VERSION 5.7 ;
  NOWIREEXTENSIONATPIN ON ;
  DIVIDERCHAR "/" ;
  BUSBITCHARS "[]" ;
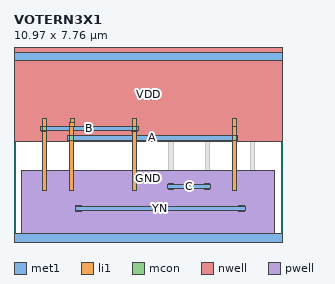
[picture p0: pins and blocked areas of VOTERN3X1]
MACRO VOTERN3X1
  CLASS CORE ;
  FOREIGN VOTERN3X1 ;
  ORIGIN 0.000 0.000 ;
  SIZE 10.970 BY 7.760 ;
  SYMMETRY X Y ;
  SITE unitrh ;
  PIN YN
    DIRECTION OUTPUT ;
    USE SIGNAL ;
    ANTENNADIFFAREA 1.734950 ;
    PORT
      LAYER met1 ;
        RECT 2.525 1.445 2.755 1.475 ;
        RECT 5.855 1.445 6.085 1.475 ;
        RECT 9.185 1.445 9.415 1.475 ;
        RECT 2.495 1.275 9.445 1.445 ;
        RECT 2.525 1.245 2.755 1.275 ;
        RECT 5.855 1.245 6.085 1.275 ;
        RECT 9.185 1.245 9.415 1.275 ;
    END
  END YN
  PIN A
    DIRECTION INPUT ;
    USE SIGNAL ;
    ANTENNAGATEAREA 2.053700 ;
    PORT
      LAYER met1 ;
        RECT 2.225 4.335 2.455 4.365 ;
        RECT 8.885 4.335 9.115 4.365 ;
        RECT 2.195 4.165 9.145 4.335 ;
        RECT 2.225 4.135 2.455 4.165 ;
        RECT 8.885 4.135 9.115 4.165 ;
    END
    PORT
      LAYER li1 ;
        RECT 2.295 4.890 2.465 5.050 ;
        RECT 2.255 4.720 2.465 4.890 ;
        RECT 2.255 2.095 2.425 4.720 ;
      LAYER mcon ;
        RECT 2.255 4.165 2.425 4.335 ;
    END
    PORT
      LAYER li1 ;
        RECT 8.915 4.720 9.105 5.050 ;
        RECT 8.915 2.095 9.085 4.720 ;
      LAYER mcon ;
        RECT 8.915 4.165 9.085 4.335 ;
    END
  END A
  PIN B
    DIRECTION INPUT ;
    USE SIGNAL ;
    ANTENNAGATEAREA 2.066500 ;
    PORT
      LAYER met1 ;
        RECT 1.115 4.705 1.345 4.735 ;
        RECT 4.815 4.705 5.045 4.735 ;
        RECT 1.085 4.535 5.075 4.705 ;
        RECT 1.115 4.505 1.345 4.535 ;
        RECT 4.815 4.505 5.045 4.535 ;
    END
    PORT
      LAYER li1 ;
        RECT 1.145 2.095 1.315 5.050 ;
      LAYER mcon ;
        RECT 1.145 4.535 1.315 4.705 ;
    END
    PORT
      LAYER li1 ;
        RECT 4.845 2.095 5.015 5.050 ;
      LAYER mcon ;
        RECT 4.845 4.535 5.015 4.705 ;
    END
  END B
  PIN C
    DIRECTION INPUT ;
    USE SIGNAL ;
    ANTENNAGATEAREA 2.060500 ;
    PORT
      LAYER met1 ;
        RECT 6.295 2.345 6.525 2.375 ;
        RECT 7.775 2.345 8.005 2.375 ;
        RECT 6.265 2.175 8.035 2.345 ;
        RECT 6.295 2.145 6.525 2.175 ;
        RECT 7.775 2.145 8.005 2.175 ;
    END
  END C
  PIN VDD
    DIRECTION INOUT ;
    USE POWER ;
    SHAPE ABUTMENT ;
    PORT
      LAYER nwell ;
        RECT 0.000 4.110 10.970 7.940 ;
      LAYER met1 ;
        RECT 0.000 7.410 10.970 7.760 ;
    END
  END VDD
  PIN GND
    DIRECTION INOUT ;
    USE GROUND ;
    SHAPE ABUTMENT ;
    PORT
      LAYER pwell ;
        RECT 0.320 0.000 10.650 2.900 ;
      LAYER met1 ;
        RECT 0.000 0.000 10.970 0.350 ;
    END
  END GND
  OBS
      LAYER li1 ;
        RECT 0.000 7.410 10.970 7.760 ;
        RECT 0.320 4.290 0.660 7.410 ;
        RECT 1.195 5.305 1.365 7.410 ;
        RECT 1.635 7.005 1.815 7.175 ;
        RECT 1.635 5.475 1.805 7.005 ;
        RECT 2.075 5.735 2.245 7.410 ;
        RECT 2.515 5.475 2.685 7.175 ;
        RECT 1.635 5.305 2.685 5.475 ;
        RECT 2.955 5.305 3.125 7.410 ;
        RECT 2.515 5.225 2.685 5.305 ;
        RECT 3.650 4.290 3.990 7.410 ;
        RECT 4.515 7.005 6.445 7.175 ;
        RECT 4.515 5.225 4.685 7.005 ;
        RECT 4.955 5.475 5.125 6.745 ;
        RECT 5.395 5.735 5.565 7.005 ;
        RECT 5.835 5.475 6.005 6.745 ;
        RECT 6.275 5.555 6.445 7.005 ;
        RECT 4.955 5.305 6.005 5.475 ;
        RECT 5.835 5.225 6.005 5.305 ;
        RECT 0.320 0.350 0.660 2.900 ;
        RECT 1.100 1.845 1.270 1.925 ;
        RECT 2.070 1.845 2.240 1.925 ;
        RECT 1.100 1.675 2.240 1.845 ;
        RECT 1.100 0.545 1.270 1.675 ;
        RECT 1.585 0.350 1.755 1.300 ;
        RECT 2.070 0.795 2.240 1.675 ;
        RECT 2.555 1.350 2.725 1.525 ;
        RECT 2.550 1.195 2.725 1.350 ;
        RECT 2.550 1.015 2.720 1.195 ;
        RECT 3.040 0.795 3.210 1.925 ;
        RECT 2.070 0.625 3.210 0.795 ;
        RECT 2.070 0.545 2.240 0.625 ;
        RECT 3.040 0.545 3.210 0.625 ;
        RECT 3.650 0.350 3.990 2.900 ;
        RECT 6.325 2.095 6.495 5.050 ;
        RECT 6.980 4.290 7.320 7.410 ;
        RECT 7.855 7.005 9.785 7.175 ;
        RECT 7.855 5.225 8.025 7.005 ;
        RECT 8.295 5.475 8.465 6.745 ;
        RECT 8.735 5.735 8.905 7.005 ;
        RECT 9.175 5.475 9.345 6.745 ;
        RECT 9.615 5.735 9.785 7.005 ;
        RECT 8.295 5.305 9.825 5.475 ;
        RECT 4.430 1.845 4.600 1.925 ;
        RECT 5.400 1.845 5.570 1.925 ;
        RECT 4.430 1.675 5.570 1.845 ;
        RECT 4.430 0.545 4.600 1.675 ;
        RECT 4.915 0.350 5.085 1.300 ;
        RECT 5.400 0.795 5.570 1.675 ;
        RECT 5.885 1.015 6.055 1.525 ;
        RECT 6.370 0.795 6.540 1.925 ;
        RECT 5.400 0.625 6.540 0.795 ;
        RECT 5.400 0.545 5.570 0.625 ;
        RECT 6.370 0.545 6.540 0.625 ;
        RECT 6.980 0.350 7.320 2.900 ;
        RECT 7.805 2.095 7.975 5.050 ;
        RECT 7.760 1.845 7.930 1.925 ;
        RECT 8.730 1.845 8.900 1.925 ;
        RECT 9.655 1.910 9.825 5.305 ;
        RECT 10.310 4.290 10.650 7.410 ;
        RECT 7.760 1.675 8.900 1.845 ;
        RECT 7.760 0.545 7.930 1.675 ;
        RECT 8.245 0.350 8.415 1.300 ;
        RECT 8.730 0.795 8.900 1.675 ;
        RECT 9.215 1.740 9.825 1.910 ;
        RECT 9.215 1.015 9.385 1.740 ;
        RECT 9.700 0.795 9.870 1.570 ;
        RECT 8.730 0.625 9.870 0.795 ;
        RECT 8.730 0.545 8.900 0.625 ;
        RECT 9.700 0.545 9.870 0.625 ;
        RECT 10.310 0.350 10.650 2.900 ;
        RECT 0.000 0.000 10.970 0.350 ;
      LAYER mcon ;
        RECT 0.775 7.495 0.945 7.665 ;
        RECT 1.145 7.495 1.315 7.665 ;
        RECT 1.515 7.495 1.685 7.665 ;
        RECT 1.885 7.495 2.055 7.665 ;
        RECT 2.255 7.495 2.425 7.665 ;
        RECT 2.625 7.495 2.795 7.665 ;
        RECT 2.995 7.495 3.165 7.665 ;
        RECT 3.365 7.495 3.535 7.665 ;
        RECT 4.105 7.495 4.275 7.665 ;
        RECT 4.475 7.495 4.645 7.665 ;
        RECT 4.845 7.495 5.015 7.665 ;
        RECT 5.215 7.495 5.385 7.665 ;
        RECT 5.585 7.495 5.755 7.665 ;
        RECT 5.955 7.495 6.125 7.665 ;
        RECT 6.325 7.495 6.495 7.665 ;
        RECT 6.695 7.495 6.865 7.665 ;
        RECT 7.435 7.495 7.605 7.665 ;
        RECT 7.805 7.495 7.975 7.665 ;
        RECT 8.175 7.495 8.345 7.665 ;
        RECT 8.545 7.495 8.715 7.665 ;
        RECT 8.915 7.495 9.085 7.665 ;
        RECT 9.285 7.495 9.455 7.665 ;
        RECT 9.655 7.495 9.825 7.665 ;
        RECT 10.025 7.495 10.195 7.665 ;
        RECT 2.515 5.305 2.685 5.475 ;
        RECT 4.515 5.305 4.685 5.475 ;
        RECT 5.835 5.305 6.005 5.475 ;
        RECT 2.555 1.275 2.725 1.445 ;
        RECT 7.855 5.305 8.025 5.475 ;
        RECT 6.325 2.175 6.495 2.345 ;
        RECT 5.885 1.275 6.055 1.445 ;
        RECT 7.805 2.175 7.975 2.345 ;
        RECT 9.215 1.275 9.385 1.445 ;
        RECT 0.775 0.095 0.945 0.265 ;
        RECT 1.145 0.095 1.315 0.265 ;
        RECT 1.515 0.095 1.685 0.265 ;
        RECT 1.885 0.095 2.055 0.265 ;
        RECT 2.255 0.095 2.425 0.265 ;
        RECT 2.625 0.095 2.795 0.265 ;
        RECT 2.995 0.095 3.165 0.265 ;
        RECT 3.365 0.095 3.535 0.265 ;
        RECT 4.105 0.095 4.275 0.265 ;
        RECT 4.475 0.095 4.645 0.265 ;
        RECT 4.845 0.095 5.015 0.265 ;
        RECT 5.215 0.095 5.385 0.265 ;
        RECT 5.585 0.095 5.755 0.265 ;
        RECT 5.955 0.095 6.125 0.265 ;
        RECT 6.325 0.095 6.495 0.265 ;
        RECT 6.695 0.095 6.865 0.265 ;
        RECT 7.435 0.095 7.605 0.265 ;
        RECT 7.805 0.095 7.975 0.265 ;
        RECT 8.175 0.095 8.345 0.265 ;
        RECT 8.545 0.095 8.715 0.265 ;
        RECT 8.915 0.095 9.085 0.265 ;
        RECT 9.285 0.095 9.455 0.265 ;
        RECT 9.655 0.095 9.825 0.265 ;
        RECT 10.025 0.095 10.195 0.265 ;
      LAYER met1 ;
        RECT 2.485 5.475 2.715 5.505 ;
        RECT 4.485 5.475 4.715 5.505 ;
        RECT 5.805 5.475 6.035 5.505 ;
        RECT 7.825 5.475 8.055 5.505 ;
        RECT 2.455 5.305 4.745 5.475 ;
        RECT 5.775 5.305 8.085 5.475 ;
        RECT 2.485 5.275 2.715 5.305 ;
        RECT 4.485 5.275 4.715 5.305 ;
        RECT 5.805 5.275 6.035 5.305 ;
        RECT 7.825 5.275 8.055 5.305 ;
  END
END VOTERN3X1
END LIBRARY

